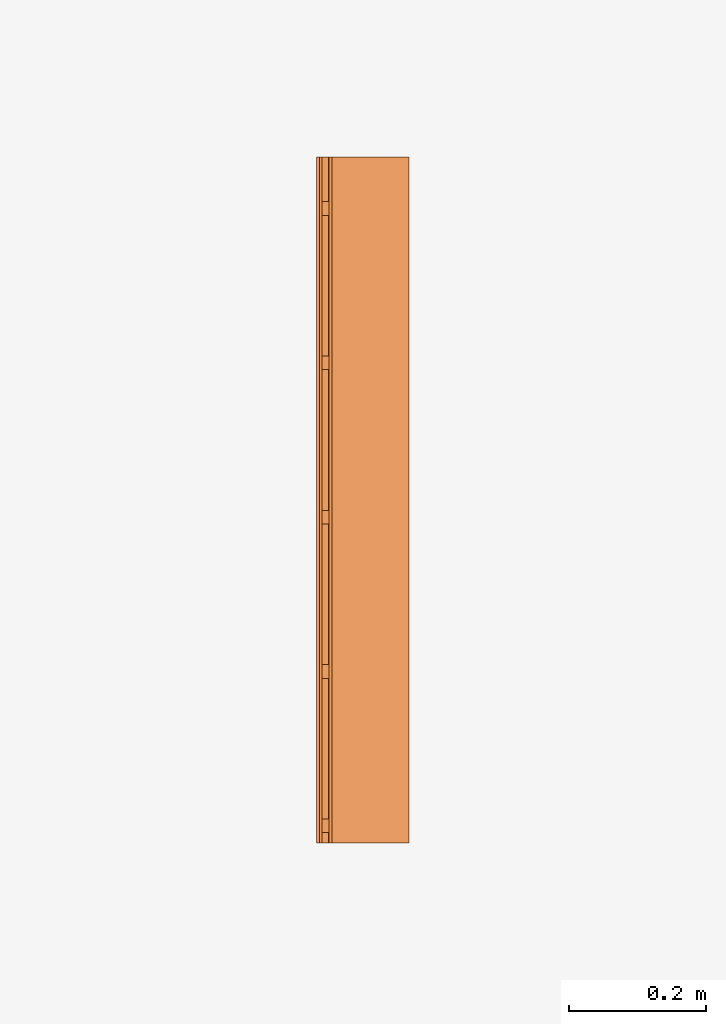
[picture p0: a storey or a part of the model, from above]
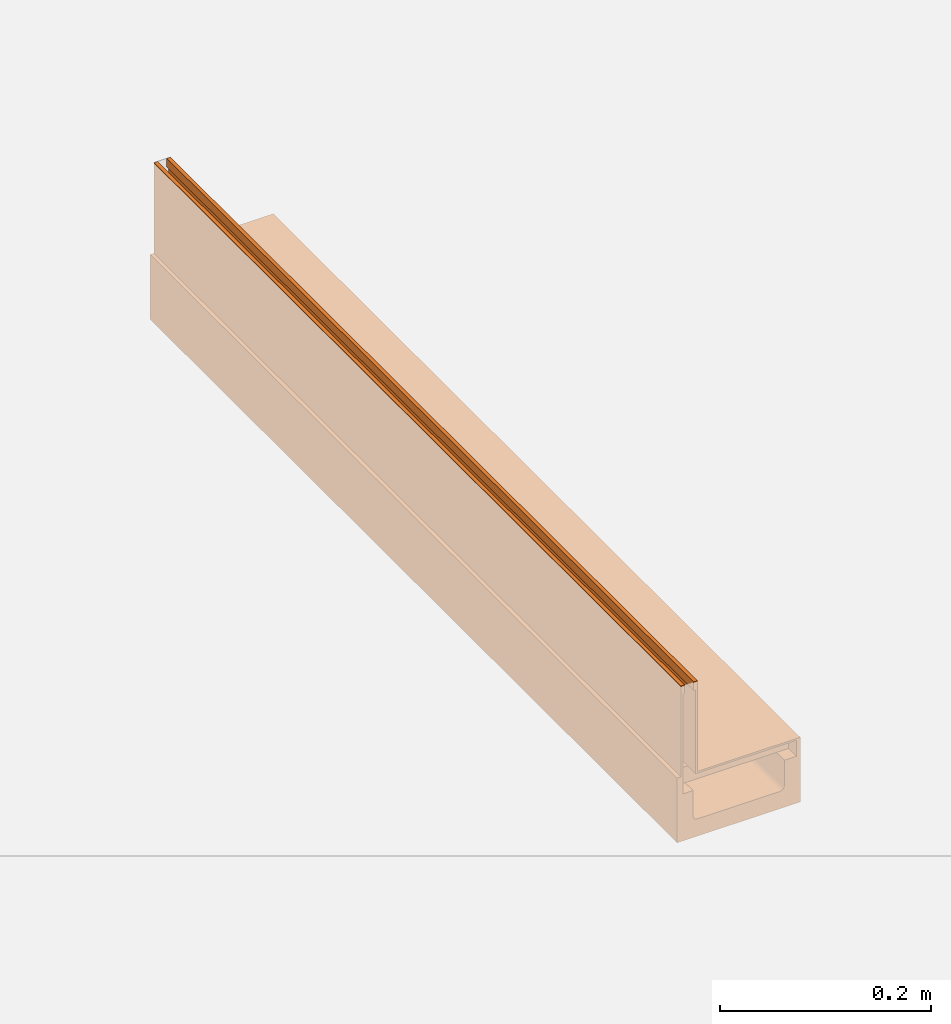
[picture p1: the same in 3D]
Properties of the parts of a building model (IFC2X3)

# File
Description: ViewDefinition [CoordinationView]
File name: 24075.ifc
Time: 2013-10-30T12:01:00
Written by: Autodesk Revit 2013
Made in: 20120221_2030(x64)

# IfcProject, Project Number
LongName: Project Name; Phase: Project Status

# IfcSite, Default
RefLatitude: 42, 21, 30, 344238; RefLongitude: -71, -3, -35, -194702; RefElevation: 0 mm

# IfcBuilding
Pset_BuildingCommon - NumberOfStoreys: 1
Other - Project Status: Project Status; Project Issue Date: Issue Date; Project Name: Project Name; Project Address: ## Street City, State Zip; Client Name: Owner; Project Number: Project Number

# IfcBuildingStorey, Level 1
LongName: Level 1; Elevation: 0 mm
Constraints - Elevation Base: 0; Elevation: 0 mm
Graphics - Symbol: M_Level Head - Circle: M_Level Head - Circle; Color: 0; Line Weight: 1; Line Pattern: Center; Symbol at End 2 Default: yes; Symbol at End 1 Default: no
Dimensions - Computation Height: 0 mm
Identity Data - Building Story: yes; Name: Level 1; Structural: no

# IfcBuildingElementProxy: 24075 - No 075 Constant Depth Channel - 1000mm LG - Invert Depth 55mm, Civil-Drainage-Channel-ACO-MultiDrain-M100DS-Brickslot-Channel-System:24075 - No 075 Constant Depth Channel - 1000mm LG - Invert Depth 55mm:24075 - No 075 Constant Depth Channel - 1000mm LG - Invert Depth 55mm:196059
In: Level 1
Material: Stainless Steel (F), Vienite® Synthetic Resin Concrete
Dimensions - Brickslot Void Length: 1000 mm; Brickslot Void Depth: 0 mm; EndCap Position: 1000 mm; FloorCut_Length: -1000 mm; Custom_Void_length: 0 mm; Volume: 4900390 mm3; Length: 1000 mm; Brickslot Access Unit Void Bottom Depth: -6605 mm; Brickslot Access Unit Void Depth: -6500 mm; FloorCut_Width: 135 mm; ShallowInvDepth: 55 mm; FloorCut_Depth: 75 mm; GratingLength: -1000 mm; ShallowOverallDepth: 75 mm; Floor Cut Gap: 105 mm; EndCap_Height: 75 mm; Length Drain: -1000 mm; Brickslot Access Unit Floor Cut Length: 500 mm; InvDepth: 80 mm; Depth: 150 mm
Construction - 23477_Load Class C250 & D400_Brickslot_Access Unit_Stainless Steel_500mm Long: no; 23404_Universal Endcap (Male End): no; 23476_Load Class C250 & D400_Brickslot Grating_Stainless Steel_500mm Long: no; 23475_Load Class C250 & D400_Brickslot Grating_Stainless Steel_1000mm Long: yes; 23404_Universal Endcap (Female End): no; Constant Depth Channel: no; 23410_Sump Unit: no; Shallow Depth Channel: yes; Constant Depth Junction Channel: no; Shallow Depth Channel with seal: no
Constraints - Level: Level: Level 1; Moves With Nearby Elements: no
Phasing - Phase Created: New Construction
Pset_BuildingElementProxyCommon - Reference: 24075 - No 075 Constant Depth Channel - 1000mm LG - Invert Depth 55mm
Identity Data - e-mail Technical: technical@aco.co.uk; Watermark 1: This file is the property of ACO Technologies PLC; Watermarked With: BIM Manager Premium Suite; OmniClass Title: Rainwater Removal; Type Comments: ACO MultiDrain M100DS No 075 Constant Depth Shallow Channel 1000mm Long; Watermark 2: This file is water marked and users are prohibited to reproduce, adapt, distribute this information; Assembly Description: Rain Water Drainage; Product brochure: http://www.aco.co.uk/download.php?id=173; e-mail Sales: customersupport@aco.co.uk; Cost: 0; Address: ACO Business Park, Hitchin Road, Shefford, Bedfordshire, United Kingdom SG17 5TE; Model: ACO MultiDrain MDS Brickslot- M100DS; Assembly Code: D2040; Price: POA - contact ACO; Model Description: Channel drainage system; OmniClass Number: 23.70.50.24; Product Page URL: http://www.aco.co.uk/product_detail.php?id=58; Watermarked By: www.aco.co.uk; Fax: +44 (0)1462 815895; Product Code: 24075; URL: www.aco.co.uk; Telephone: +44 (0)1462 816666; Manufacturer: ACO Technologies plc - ACO Water Management Division; Installation guidelines: http://www.aco.co.uk/download.php?id=173; Maintenance guidelines: http://www.aco.co.uk/download.php?id=173
Data - Concrete Surround Volume - Load Class A 15 - Concrete Pavement: 0.05m³/m; Concrete Surround Volume - Load Class D 400 - Concrete Pavement: 0.14m³/m; Hydraulic Performance: http://www.aco.co.uk/download.php?id=173; Product Dimensions: 1000mm x 135mm x 75mm (LxWxH); Pre-formed Outlet Ø: N/A; ACO Hydraulic Design Software: http://www.acodesign.co.uk; Channel C.S.A: 0.0034m²; Installation - Concrete Grade: Refer to brochure; Load Class: A 15 - D400; Product Standard: BS EN 1433:2002, CE marked; Product Weight: 10.9 Kg; Invert Depth: 55mm; Concrete Surround Volume - Load Class B 125 - C 250 - Concrete Pavement: 0.09m³/m
Other - Revision: 1; Created By: www.aco.co.uk
Materials and Finishes - Edge Rail Colour: Self; Edge Rail Material: Stainless Steel Grade 304; Channel Material: Vienite® Synthetic Resin Concrete; Channel Colour: Brown
Green Building Properties - Channel Recycled Material Content: 20% minimum; Edge Rail Recycled Material Content: Between 40% - 90%; Channel Recyclable: Fully recyclable; Edge Rail Recyclable: Fully recyclable
Model Properties - Brickslot Grating Product code 23475: Load Class C250/D400 - Brickslot Stainless Steel - 1000mm long x 105mm high -10mm Slot- Intake area - 1000mm²/m - 6.6 Kg; End Cap Product code 23404: No 306 Universl End Cap - 135mm wide x 300mm long - Spigot Ø110mm x 50mm long - Silver - Polypropylene - 0.16kg; Brickslot Access Unit Product code 23477: Load Class C250/D400 - Brickslot Access Unit Stainless Steel - 500mm long x 105mm high -10mm Slot- Intake area - 1000mm²/m - 6.4 Kg; Brickslot Grating Product code 23476: Load Class C250/D400 - Brickslot Stainless Steel - 500mm long x 105mm high -10mm Slot- Intake area - 1000mm²/m - 3.3 Kg
General - SerialNumber: 0; TagNumber: 0

# IfcOpeningElement: Recess (2)
In: Level 1
Dimensions - Volume: 9987985000 mm3; Thickness: 400 mm; Perimeter: 20000 mm; Area: 25000000 mm2
Structural - Structural: no; Enable Analytical Model: no
Constraints - Height Offset From Level: 0 mm; Related to Mass: no; Room Bounding: yes; Level: Level: Level 1
Phasing - Phase Created: New Construction
Construction - Function: 0; Default Thickness: 400 mm
Analytical Properties - Heat Transfer Coefficient (U): 2.0925; Absorptance: 0.1; Thermal Resistance (R): 0.477897; Thermal mass: 543920; Roughness: 1
Materials and Finishes - Structural Material: Earth
Graphics - Coarse Scale Fill Color: 0

# IfcSlab: Floor:Generic Floor - 400mm, Floor:Generic Floor - 400mm:193825
In: Level 1
PredefinedType: FLOOR; Material: Earth 400 mm
Dimensions - Volume: 9987985000 mm3; Thickness: 400 mm; Perimeter: 20000 mm; Area: 25000000 mm2
Structural - Structural: no; Enable Analytical Model: no
Constraints - Height Offset From Level: 0 mm; Related to Mass: no; Room Bounding: yes; Level: Level: Level 1
Phasing - Phase Created: New Construction
Pset_SlabCommon - Reference: Generic Floor - 400mm; IsExternal: no; LoadBearing: yes
Construction - Function: 0; Default Thickness: 400 mm
Analytical Properties - Heat Transfer Coefficient (U): 2.0925; Absorptance: 0.1; Thermal Resistance (R): 0.477897; Thermal mass: 543920; Roughness: 1
Materials and Finishes - Structural Material: Earth
Graphics - Coarse Scale Fill Color: 0
